One B-rep face of a CAD part: STEP entity #17789.
In plain terms, the planar face has unit normal (1, 0, 0).
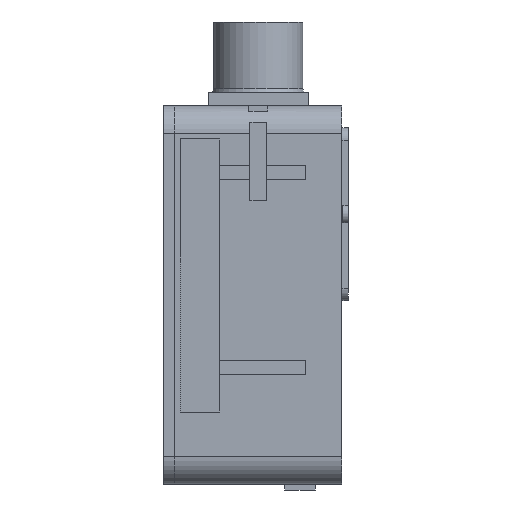
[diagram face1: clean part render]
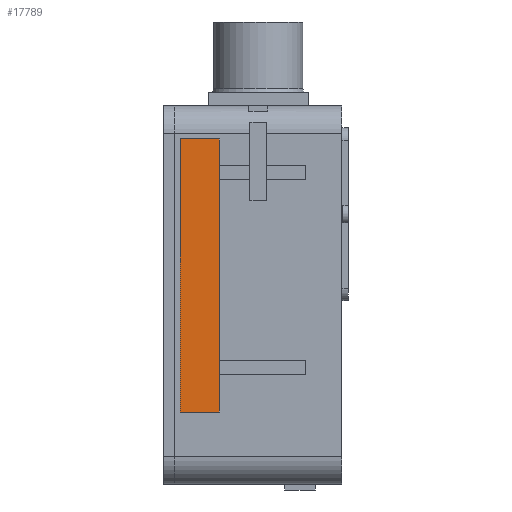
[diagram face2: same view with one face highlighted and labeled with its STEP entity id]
Its self-contained STEP definition (entity closure, numbers rounded to 3 decimals):
#4267 = PLANE('',#4268);
#4268 = AXIS2_PLACEMENT_3D('',#4269,#4270,#4271);
#4269 = CARTESIAN_POINT('',(25.,-21.,22.));
#4270 = DIRECTION('',(0.,0.,1.));
#4271 = DIRECTION('',(1.,0.,-0.));
#4295 = PLANE('',#4296);
#4296 = AXIS2_PLACEMENT_3D('',#4297,#4298,#4299);
#4297 = CARTESIAN_POINT('',(25.,28.,22.));
#4298 = DIRECTION('',(-0.,1.,0.));
#4299 = DIRECTION('',(0.,0.,1.));
#4323 = PLANE('',#4324);
#4324 = AXIS2_PLACEMENT_3D('',#4325,#4326,#4327);
#4325 = CARTESIAN_POINT('',(25.,-21.,29.));
#4326 = DIRECTION('',(0.,0.,1.));
#4327 = DIRECTION('',(1.,0.,-0.));
#4351 = PLANE('',#4352);
#4352 = AXIS2_PLACEMENT_3D('',#4353,#4354,#4355);
#4353 = CARTESIAN_POINT('',(25.,-21.,22.));
#4354 = DIRECTION('',(-0.,1.,0.));
#4355 = DIRECTION('',(0.,0.,1.));
#10728 = VERTEX_POINT('',#10729);
#10729 = CARTESIAN_POINT('',(26.,-21.,22.));
#10750 = EDGE_CURVE('',#10728,#10751,#10753,.T.);
#10751 = VERTEX_POINT('',#10752);
#10752 = CARTESIAN_POINT('',(26.,28.,22.));
#10753 = SURFACE_CURVE('',#10754,(#10758,#10765),.PCURVE_S1.);
#10754 = LINE('',#10755,#10756);
#10755 = CARTESIAN_POINT('',(26.,-21.,22.));
#10756 = VECTOR('',#10757,1.);
#10757 = DIRECTION('',(-0.,1.,0.));
#10758 = PCURVE('',#4267,#10759);
#10759 = DEFINITIONAL_REPRESENTATION('',(#10760),#10764);
#10760 = LINE('',#10761,#10762);
#10761 = CARTESIAN_POINT('',(1.,0.));
#10762 = VECTOR('',#10763,1.);
#10763 = DIRECTION('',(0.,1.));
#10764 = ( GEOMETRIC_REPRESENTATION_CONTEXT(2) 
PARAMETRIC_REPRESENTATION_CONTEXT() REPRESENTATION_CONTEXT('2D SPACE',''
  ) );
#10765 = PCURVE('',#10766,#10771);
#10766 = PLANE('',#10767);
#10767 = AXIS2_PLACEMENT_3D('',#10768,#10769,#10770);
#10768 = CARTESIAN_POINT('',(26.,-21.,22.));
#10769 = DIRECTION('',(1.,0.,-0.));
#10770 = DIRECTION('',(0.,0.,1.));
#10771 = DEFINITIONAL_REPRESENTATION('',(#10772),#10776);
#10772 = LINE('',#10773,#10774);
#10773 = CARTESIAN_POINT('',(0.,0.));
#10774 = VECTOR('',#10775,1.);
#10775 = DIRECTION('',(0.,-1.));
#10776 = ( GEOMETRIC_REPRESENTATION_CONTEXT(2) 
PARAMETRIC_REPRESENTATION_CONTEXT() REPRESENTATION_CONTEXT('2D SPACE',''
  ) );
#11039 = VERTEX_POINT('',#11040);
#11040 = CARTESIAN_POINT('',(26.,-21.,29.));
#11061 = EDGE_CURVE('',#10728,#11039,#11062,.T.);
#11062 = SURFACE_CURVE('',#11063,(#11067,#11074),.PCURVE_S1.);
#11063 = LINE('',#11064,#11065);
#11064 = CARTESIAN_POINT('',(26.,-21.,22.));
#11065 = VECTOR('',#11066,1.);
#11066 = DIRECTION('',(0.,0.,1.));
#11067 = PCURVE('',#4351,#11068);
#11068 = DEFINITIONAL_REPRESENTATION('',(#11069),#11073);
#11069 = LINE('',#11070,#11071);
#11070 = CARTESIAN_POINT('',(0.,1.));
#11071 = VECTOR('',#11072,1.);
#11072 = DIRECTION('',(1.,0.));
#11073 = ( GEOMETRIC_REPRESENTATION_CONTEXT(2) 
PARAMETRIC_REPRESENTATION_CONTEXT() REPRESENTATION_CONTEXT('2D SPACE',''
  ) );
#11074 = PCURVE('',#10766,#11075);
#11075 = DEFINITIONAL_REPRESENTATION('',(#11076),#11080);
#11076 = LINE('',#11077,#11078);
#11077 = CARTESIAN_POINT('',(0.,0.));
#11078 = VECTOR('',#11079,1.);
#11079 = DIRECTION('',(1.,0.));
#11080 = ( GEOMETRIC_REPRESENTATION_CONTEXT(2) 
PARAMETRIC_REPRESENTATION_CONTEXT() REPRESENTATION_CONTEXT('2D SPACE',''
  ) );
#11087 = EDGE_CURVE('',#11039,#11088,#11090,.T.);
#11088 = VERTEX_POINT('',#11089);
#11089 = CARTESIAN_POINT('',(26.,28.,29.));
#11090 = SURFACE_CURVE('',#11091,(#11095,#11102),.PCURVE_S1.);
#11091 = LINE('',#11092,#11093);
#11092 = CARTESIAN_POINT('',(26.,-21.,29.));
#11093 = VECTOR('',#11094,1.);
#11094 = DIRECTION('',(-0.,1.,0.));
#11095 = PCURVE('',#4323,#11096);
#11096 = DEFINITIONAL_REPRESENTATION('',(#11097),#11101);
#11097 = LINE('',#11098,#11099);
#11098 = CARTESIAN_POINT('',(1.,0.));
#11099 = VECTOR('',#11100,1.);
#11100 = DIRECTION('',(0.,1.));
#11101 = ( GEOMETRIC_REPRESENTATION_CONTEXT(2) 
PARAMETRIC_REPRESENTATION_CONTEXT() REPRESENTATION_CONTEXT('2D SPACE',''
  ) );
#11102 = PCURVE('',#10766,#11103);
#11103 = DEFINITIONAL_REPRESENTATION('',(#11104),#11108);
#11104 = LINE('',#11105,#11106);
#11105 = CARTESIAN_POINT('',(7.,0.));
#11106 = VECTOR('',#11107,1.);
#11107 = DIRECTION('',(0.,-1.));
#11108 = ( GEOMETRIC_REPRESENTATION_CONTEXT(2) 
PARAMETRIC_REPRESENTATION_CONTEXT() REPRESENTATION_CONTEXT('2D SPACE',''
  ) );
#11137 = EDGE_CURVE('',#10751,#11088,#11138,.T.);
#11138 = SURFACE_CURVE('',#11139,(#11143,#11150),.PCURVE_S1.);
#11139 = LINE('',#11140,#11141);
#11140 = CARTESIAN_POINT('',(26.,28.,22.));
#11141 = VECTOR('',#11142,1.);
#11142 = DIRECTION('',(0.,0.,1.));
#11143 = PCURVE('',#4295,#11144);
#11144 = DEFINITIONAL_REPRESENTATION('',(#11145),#11149);
#11145 = LINE('',#11146,#11147);
#11146 = CARTESIAN_POINT('',(0.,1.));
#11147 = VECTOR('',#11148,1.);
#11148 = DIRECTION('',(1.,0.));
#11149 = ( GEOMETRIC_REPRESENTATION_CONTEXT(2) 
PARAMETRIC_REPRESENTATION_CONTEXT() REPRESENTATION_CONTEXT('2D SPACE',''
  ) );
#11150 = PCURVE('',#10766,#11151);
#11151 = DEFINITIONAL_REPRESENTATION('',(#11152),#11156);
#11152 = LINE('',#11153,#11154);
#11153 = CARTESIAN_POINT('',(0.,-49.));
#11154 = VECTOR('',#11155,1.);
#11155 = DIRECTION('',(1.,0.));
#11156 = ( GEOMETRIC_REPRESENTATION_CONTEXT(2) 
PARAMETRIC_REPRESENTATION_CONTEXT() REPRESENTATION_CONTEXT('2D SPACE',''
  ) );
#17789 = ADVANCED_FACE('',(#17790),#10766,.T.);
#17790 = FACE_BOUND('',#17791,.T.);
#17791 = EDGE_LOOP('',(#17792,#17793,#17794,#17795));
#17792 = ORIENTED_EDGE('',*,*,#11061,.F.);
#17793 = ORIENTED_EDGE('',*,*,#10750,.T.);
#17794 = ORIENTED_EDGE('',*,*,#11137,.T.);
#17795 = ORIENTED_EDGE('',*,*,#11087,.F.);
